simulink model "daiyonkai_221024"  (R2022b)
settings: Solver=FixedStepAuto  StartTime=0.0  StopTime=20  FixedStep=1e-3  RelTol=1e-3
PreLoadFcn:
  | Kp=1
  | Ki=1

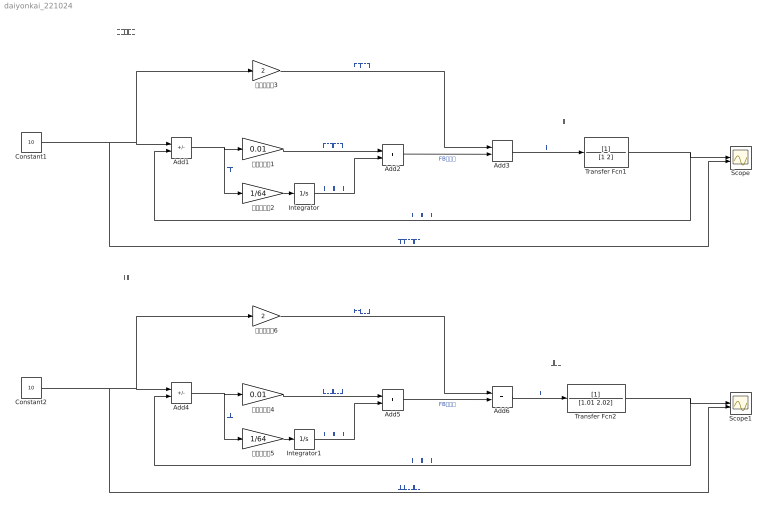
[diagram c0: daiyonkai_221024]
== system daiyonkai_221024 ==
  note: プログラム
  note: 乗り物
  note: プログラム
  note: 乗り物
  Add1 : Sum  Inputs=+-
  Add{2..3,5..6} (4 alike) : Sum
  Add4 : Sum  Inputs=+-
  Constant1 : Constant  Value=10
  Constant2 : Constant  Value=10
  Integrator : Integrator
  Integrator1 : Integrator
  Scope : Scope  NumInputPorts=2
  Scope1 : Scope  NumInputPorts=2
  Transfer Fcn1 : TransferFcn  Denominator=[1 2]
  Transfer Fcn2 : TransferFcn  Denominator=[1.01 2.02]
  比例ゲイン1 : Gain  Gain=0.01
  比例ゲイン2 : Gain  Gain=1/64
  比例ゲイン3 : Gain  Gain=2
  比例ゲイン4 : Gain  Gain=0.01
  比例ゲイン5 : Gain  Gain=1/64
  比例ゲイン6 : Gain  Gain=2
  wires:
  Transfer Fcn1/1 -> Add1/2, Scope/1  "乗り物の速度"
  Add1/1 -> 比例ゲイン2/1, 比例ゲイン1/1  "偏差"
  比例ゲイン1/1 -> Add2/1  "比例項の出力"
  Constant1/1 -> Scope/2, 比例ゲイン3/1, Add1/1  "ロボットの速度"
  比例ゲイン2/1 -> Integrator/1
  Add2/1 -> Add3/2  "FBの出力"
  Integrator/1 -> Add2/2  "積分項の出力"
  Add3/1 -> Transfer Fcn1/1  "力"
  比例ゲイン3/1 -> Add3/1  "FFの出力"
  Add4/1 -> 比例ゲイン5/1, 比例ゲイン4/1  "偏差"
  比例ゲイン4/1 -> Add5/1  "比例項の出力"
  Constant2/1 -> Scope1/2, 比例ゲイン6/1, Add4/1  "ロボットの速度"
  Add6/1 -> Transfer Fcn2/1  "力"
  比例ゲイン6/1 -> Add6/1  "FFの出力"
  Transfer Fcn2/1 -> Scope1/1, Add4/2  "乗り物の速度"
  比例ゲイン5/1 -> Integrator1/1
  Integrator1/1 -> Add5/2  "積分項の出力"
  Add5/1 -> Add6/2  "FBの出力"
